VERSION 5.7 ;
BUSBITCHARS "[]" ;
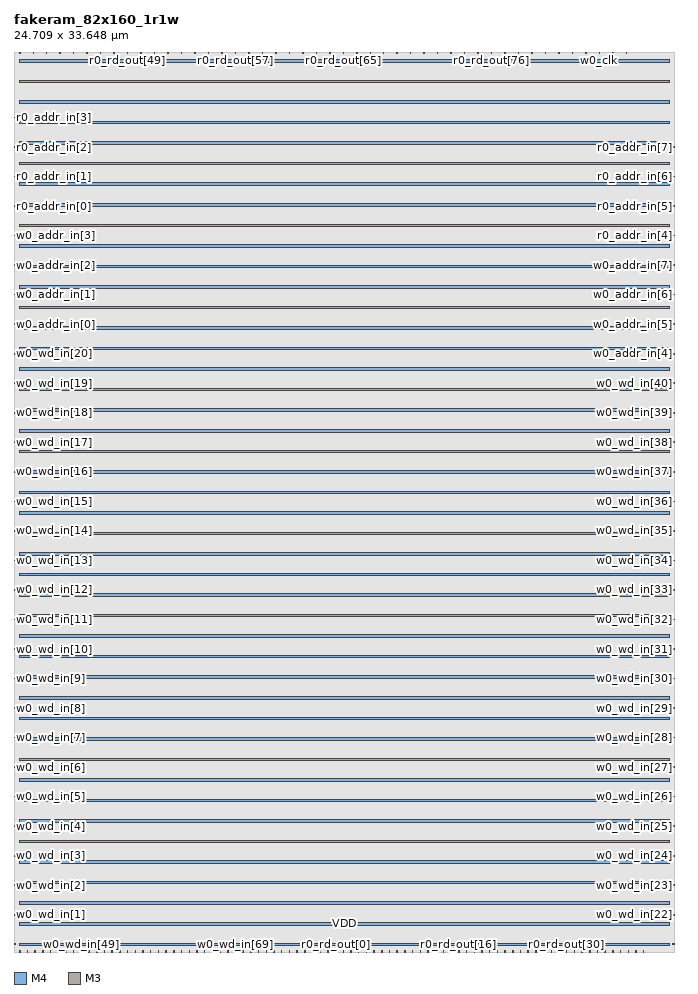
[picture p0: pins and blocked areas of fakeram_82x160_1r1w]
MACRO fakeram_82x160_1r1w
  FOREIGN fakeram_82x160_1r1w 0 0 ;
  SYMMETRY X Y R90 ;
  SIZE 24.709 BY 33.648 ;
  CLASS BLOCK ;
  PIN w0_wd_in[0]
    DIRECTION INPUT ;
    USE SIGNAL ;
    SHAPE ABUTMENT ;
    PORT
      LAYER M4 ;
      RECT 0.000 0.276 0.072 0.300 ;
    END
  END w0_wd_in[0]
  PIN w0_wd_in[1]
    DIRECTION INPUT ;
    USE SIGNAL ;
    SHAPE ABUTMENT ;
    PORT
      LAYER M4 ;
      RECT 0.000 1.380 0.072 1.404 ;
    END
  END w0_wd_in[1]
  PIN w0_wd_in[2]
    DIRECTION INPUT ;
    USE SIGNAL ;
    SHAPE ABUTMENT ;
    PORT
      LAYER M4 ;
      RECT 0.000 2.484 0.072 2.508 ;
    END
  END w0_wd_in[2]
  PIN w0_wd_in[3]
    DIRECTION INPUT ;
    USE SIGNAL ;
    SHAPE ABUTMENT ;
    PORT
      LAYER M4 ;
      RECT 0.000 3.588 0.072 3.612 ;
    END
  END w0_wd_in[3]
  PIN w0_wd_in[4]
    DIRECTION INPUT ;
    USE SIGNAL ;
    SHAPE ABUTMENT ;
    PORT
      LAYER M4 ;
      RECT 0.000 4.692 0.072 4.716 ;
    END
  END w0_wd_in[4]
  PIN w0_wd_in[5]
    DIRECTION INPUT ;
    USE SIGNAL ;
    SHAPE ABUTMENT ;
    PORT
      LAYER M4 ;
      RECT 0.000 5.796 0.072 5.820 ;
    END
  END w0_wd_in[5]
  PIN w0_wd_in[6]
    DIRECTION INPUT ;
    USE SIGNAL ;
    SHAPE ABUTMENT ;
    PORT
      LAYER M4 ;
      RECT 0.000 6.900 0.072 6.924 ;
    END
  END w0_wd_in[6]
  PIN w0_wd_in[7]
    DIRECTION INPUT ;
    USE SIGNAL ;
    SHAPE ABUTMENT ;
    PORT
      LAYER M4 ;
      RECT 0.000 8.004 0.072 8.028 ;
    END
  END w0_wd_in[7]
  PIN w0_wd_in[8]
    DIRECTION INPUT ;
    USE SIGNAL ;
    SHAPE ABUTMENT ;
    PORT
      LAYER M4 ;
      RECT 0.000 9.108 0.072 9.132 ;
    END
  END w0_wd_in[8]
  PIN w0_wd_in[9]
    DIRECTION INPUT ;
    USE SIGNAL ;
    SHAPE ABUTMENT ;
    PORT
      LAYER M4 ;
      RECT 0.000 10.212 0.072 10.236 ;
    END
  END w0_wd_in[9]
  PIN w0_wd_in[10]
    DIRECTION INPUT ;
    USE SIGNAL ;
    SHAPE ABUTMENT ;
    PORT
      LAYER M4 ;
      RECT 0.000 11.316 0.072 11.340 ;
    END
  END w0_wd_in[10]
  PIN w0_wd_in[11]
    DIRECTION INPUT ;
    USE SIGNAL ;
    SHAPE ABUTMENT ;
    PORT
      LAYER M4 ;
      RECT 0.000 12.420 0.072 12.444 ;
    END
  END w0_wd_in[11]
  PIN w0_wd_in[12]
    DIRECTION INPUT ;
    USE SIGNAL ;
    SHAPE ABUTMENT ;
    PORT
      LAYER M4 ;
      RECT 0.000 13.524 0.072 13.548 ;
    END
  END w0_wd_in[12]
  PIN w0_wd_in[13]
    DIRECTION INPUT ;
    USE SIGNAL ;
    SHAPE ABUTMENT ;
    PORT
      LAYER M4 ;
      RECT 0.000 14.628 0.072 14.652 ;
    END
  END w0_wd_in[13]
  PIN w0_wd_in[14]
    DIRECTION INPUT ;
    USE SIGNAL ;
    SHAPE ABUTMENT ;
    PORT
      LAYER M4 ;
      RECT 0.000 15.732 0.072 15.756 ;
    END
  END w0_wd_in[14]
  PIN w0_wd_in[15]
    DIRECTION INPUT ;
    USE SIGNAL ;
    SHAPE ABUTMENT ;
    PORT
      LAYER M4 ;
      RECT 0.000 16.836 0.072 16.860 ;
    END
  END w0_wd_in[15]
  PIN w0_wd_in[16]
    DIRECTION INPUT ;
    USE SIGNAL ;
    SHAPE ABUTMENT ;
    PORT
      LAYER M4 ;
      RECT 0.000 17.940 0.072 17.964 ;
    END
  END w0_wd_in[16]
  PIN w0_wd_in[17]
    DIRECTION INPUT ;
    USE SIGNAL ;
    SHAPE ABUTMENT ;
    PORT
      LAYER M4 ;
      RECT 0.000 19.044 0.072 19.068 ;
    END
  END w0_wd_in[17]
  PIN w0_wd_in[18]
    DIRECTION INPUT ;
    USE SIGNAL ;
    SHAPE ABUTMENT ;
    PORT
      LAYER M4 ;
      RECT 0.000 20.148 0.072 20.172 ;
    END
  END w0_wd_in[18]
  PIN w0_wd_in[19]
    DIRECTION INPUT ;
    USE SIGNAL ;
    SHAPE ABUTMENT ;
    PORT
      LAYER M4 ;
      RECT 0.000 21.252 0.072 21.276 ;
    END
  END w0_wd_in[19]
  PIN w0_wd_in[20]
    DIRECTION INPUT ;
    USE SIGNAL ;
    SHAPE ABUTMENT ;
    PORT
      LAYER M4 ;
      RECT 0.000 22.356 0.072 22.380 ;
    END
  END w0_wd_in[20]
  PIN w0_wd_in[21]
    DIRECTION INPUT ;
    USE SIGNAL ;
    SHAPE ABUTMENT ;
    PORT
      LAYER M4 ;
      RECT 24.637 0.276 24.709 0.300 ;
    END
  END w0_wd_in[21]
  PIN w0_wd_in[22]
    DIRECTION INPUT ;
    USE SIGNAL ;
    SHAPE ABUTMENT ;
    PORT
      LAYER M4 ;
      RECT 24.637 1.380 24.709 1.404 ;
    END
  END w0_wd_in[22]
  PIN w0_wd_in[23]
    DIRECTION INPUT ;
    USE SIGNAL ;
    SHAPE ABUTMENT ;
    PORT
      LAYER M4 ;
      RECT 24.637 2.484 24.709 2.508 ;
    END
  END w0_wd_in[23]
  PIN w0_wd_in[24]
    DIRECTION INPUT ;
    USE SIGNAL ;
    SHAPE ABUTMENT ;
    PORT
      LAYER M4 ;
      RECT 24.637 3.588 24.709 3.612 ;
    END
  END w0_wd_in[24]
  PIN w0_wd_in[25]
    DIRECTION INPUT ;
    USE SIGNAL ;
    SHAPE ABUTMENT ;
    PORT
      LAYER M4 ;
      RECT 24.637 4.692 24.709 4.716 ;
    END
  END w0_wd_in[25]
  PIN w0_wd_in[26]
    DIRECTION INPUT ;
    USE SIGNAL ;
    SHAPE ABUTMENT ;
    PORT
      LAYER M4 ;
      RECT 24.637 5.796 24.709 5.820 ;
    END
  END w0_wd_in[26]
  PIN w0_wd_in[27]
    DIRECTION INPUT ;
    USE SIGNAL ;
    SHAPE ABUTMENT ;
    PORT
      LAYER M4 ;
      RECT 24.637 6.900 24.709 6.924 ;
    END
  END w0_wd_in[27]
  PIN w0_wd_in[28]
    DIRECTION INPUT ;
    USE SIGNAL ;
    SHAPE ABUTMENT ;
    PORT
      LAYER M4 ;
      RECT 24.637 8.004 24.709 8.028 ;
    END
  END w0_wd_in[28]
  PIN w0_wd_in[29]
    DIRECTION INPUT ;
    USE SIGNAL ;
    SHAPE ABUTMENT ;
    PORT
      LAYER M4 ;
      RECT 24.637 9.108 24.709 9.132 ;
    END
  END w0_wd_in[29]
  PIN w0_wd_in[30]
    DIRECTION INPUT ;
    USE SIGNAL ;
    SHAPE ABUTMENT ;
    PORT
      LAYER M4 ;
      RECT 24.637 10.212 24.709 10.236 ;
    END
  END w0_wd_in[30]
  PIN w0_wd_in[31]
    DIRECTION INPUT ;
    USE SIGNAL ;
    SHAPE ABUTMENT ;
    PORT
      LAYER M4 ;
      RECT 24.637 11.316 24.709 11.340 ;
    END
  END w0_wd_in[31]
  PIN w0_wd_in[32]
    DIRECTION INPUT ;
    USE SIGNAL ;
    SHAPE ABUTMENT ;
    PORT
      LAYER M4 ;
      RECT 24.637 12.420 24.709 12.444 ;
    END
  END w0_wd_in[32]
  PIN w0_wd_in[33]
    DIRECTION INPUT ;
    USE SIGNAL ;
    SHAPE ABUTMENT ;
    PORT
      LAYER M4 ;
      RECT 24.637 13.524 24.709 13.548 ;
    END
  END w0_wd_in[33]
  PIN w0_wd_in[34]
    DIRECTION INPUT ;
    USE SIGNAL ;
    SHAPE ABUTMENT ;
    PORT
      LAYER M4 ;
      RECT 24.637 14.628 24.709 14.652 ;
    END
  END w0_wd_in[34]
  PIN w0_wd_in[35]
    DIRECTION INPUT ;
    USE SIGNAL ;
    SHAPE ABUTMENT ;
    PORT
      LAYER M4 ;
      RECT 24.637 15.732 24.709 15.756 ;
    END
  END w0_wd_in[35]
  PIN w0_wd_in[36]
    DIRECTION INPUT ;
    USE SIGNAL ;
    SHAPE ABUTMENT ;
    PORT
      LAYER M4 ;
      RECT 24.637 16.836 24.709 16.860 ;
    END
  END w0_wd_in[36]
  PIN w0_wd_in[37]
    DIRECTION INPUT ;
    USE SIGNAL ;
    SHAPE ABUTMENT ;
    PORT
      LAYER M4 ;
      RECT 24.637 17.940 24.709 17.964 ;
    END
  END w0_wd_in[37]
  PIN w0_wd_in[38]
    DIRECTION INPUT ;
    USE SIGNAL ;
    SHAPE ABUTMENT ;
    PORT
      LAYER M4 ;
      RECT 24.637 19.044 24.709 19.068 ;
    END
  END w0_wd_in[38]
  PIN w0_wd_in[39]
    DIRECTION INPUT ;
    USE SIGNAL ;
    SHAPE ABUTMENT ;
    PORT
      LAYER M4 ;
      RECT 24.637 20.148 24.709 20.172 ;
    END
  END w0_wd_in[39]
  PIN w0_wd_in[40]
    DIRECTION INPUT ;
    USE SIGNAL ;
    SHAPE ABUTMENT ;
    PORT
      LAYER M4 ;
      RECT 24.637 21.252 24.709 21.276 ;
    END
  END w0_wd_in[40]
  PIN w0_wd_in[41]
    DIRECTION OUTPUT ;
    USE SIGNAL ;
    SHAPE ABUTMENT ;
    PORT
      LAYER M3 ;
      RECT 0.207 0.000 0.225 0.054 ;
    END
  END w0_wd_in[41]
  PIN w0_wd_in[42]
    DIRECTION OUTPUT ;
    USE SIGNAL ;
    SHAPE ABUTMENT ;
    PORT
      LAYER M3 ;
      RECT 0.495 0.000 0.513 0.054 ;
    END
  END w0_wd_in[42]
  PIN w0_wd_in[43]
    DIRECTION OUTPUT ;
    USE SIGNAL ;
    SHAPE ABUTMENT ;
    PORT
      LAYER M3 ;
      RECT 0.783 0.000 0.801 0.054 ;
    END
  END w0_wd_in[43]
  PIN w0_wd_in[44]
    DIRECTION OUTPUT ;
    USE SIGNAL ;
    SHAPE ABUTMENT ;
    PORT
      LAYER M3 ;
      RECT 1.071 0.000 1.089 0.054 ;
    END
  END w0_wd_in[44]
  PIN w0_wd_in[45]
    DIRECTION OUTPUT ;
    USE SIGNAL ;
    SHAPE ABUTMENT ;
    PORT
      LAYER M3 ;
      RECT 1.359 0.000 1.377 0.054 ;
    END
  END w0_wd_in[45]
  PIN w0_wd_in[46]
    DIRECTION OUTPUT ;
    USE SIGNAL ;
    SHAPE ABUTMENT ;
    PORT
      LAYER M3 ;
      RECT 1.647 0.000 1.665 0.054 ;
    END
  END w0_wd_in[46]
  PIN w0_wd_in[47]
    DIRECTION OUTPUT ;
    USE SIGNAL ;
    SHAPE ABUTMENT ;
    PORT
      LAYER M3 ;
      RECT 1.935 0.000 1.953 0.054 ;
    END
  END w0_wd_in[47]
  PIN w0_wd_in[48]
    DIRECTION OUTPUT ;
    USE SIGNAL ;
    SHAPE ABUTMENT ;
    PORT
      LAYER M3 ;
      RECT 2.223 0.000 2.241 0.054 ;
    END
  END w0_wd_in[48]
  PIN w0_wd_in[49]
    DIRECTION OUTPUT ;
    USE SIGNAL ;
    SHAPE ABUTMENT ;
    PORT
      LAYER M3 ;
      RECT 2.511 0.000 2.529 0.054 ;
    END
  END w0_wd_in[49]
  PIN w0_wd_in[50]
    DIRECTION OUTPUT ;
    USE SIGNAL ;
    SHAPE ABUTMENT ;
    PORT
      LAYER M3 ;
      RECT 2.799 0.000 2.817 0.054 ;
    END
  END w0_wd_in[50]
  PIN w0_wd_in[51]
    DIRECTION OUTPUT ;
    USE SIGNAL ;
    SHAPE ABUTMENT ;
    PORT
      LAYER M3 ;
      RECT 3.087 0.000 3.105 0.054 ;
    END
  END w0_wd_in[51]
  PIN w0_wd_in[52]
    DIRECTION OUTPUT ;
    USE SIGNAL ;
    SHAPE ABUTMENT ;
    PORT
      LAYER M3 ;
      RECT 3.375 0.000 3.393 0.054 ;
    END
  END w0_wd_in[52]
  PIN w0_wd_in[53]
    DIRECTION OUTPUT ;
    USE SIGNAL ;
    SHAPE ABUTMENT ;
    PORT
      LAYER M3 ;
      RECT 3.663 0.000 3.681 0.054 ;
    END
  END w0_wd_in[53]
  PIN w0_wd_in[54]
    DIRECTION OUTPUT ;
    USE SIGNAL ;
    SHAPE ABUTMENT ;
    PORT
      LAYER M3 ;
      RECT 3.951 0.000 3.969 0.054 ;
    END
  END w0_wd_in[54]
  PIN w0_wd_in[55]
    DIRECTION OUTPUT ;
    USE SIGNAL ;
    SHAPE ABUTMENT ;
    PORT
      LAYER M3 ;
      RECT 4.239 0.000 4.257 0.054 ;
    END
  END w0_wd_in[55]
  PIN w0_wd_in[56]
    DIRECTION OUTPUT ;
    USE SIGNAL ;
    SHAPE ABUTMENT ;
    PORT
      LAYER M3 ;
      RECT 4.527 0.000 4.545 0.054 ;
    END
  END w0_wd_in[56]
  PIN w0_wd_in[57]
    DIRECTION OUTPUT ;
    USE SIGNAL ;
    SHAPE ABUTMENT ;
    PORT
      LAYER M3 ;
      RECT 4.815 0.000 4.833 0.054 ;
    END
  END w0_wd_in[57]
  PIN w0_wd_in[58]
    DIRECTION OUTPUT ;
    USE SIGNAL ;
    SHAPE ABUTMENT ;
    PORT
      LAYER M3 ;
      RECT 5.103 0.000 5.121 0.054 ;
    END
  END w0_wd_in[58]
  PIN w0_wd_in[59]
    DIRECTION OUTPUT ;
    USE SIGNAL ;
    SHAPE ABUTMENT ;
    PORT
      LAYER M3 ;
      RECT 5.391 0.000 5.409 0.054 ;
    END
  END w0_wd_in[59]
  PIN w0_wd_in[60]
    DIRECTION OUTPUT ;
    USE SIGNAL ;
    SHAPE ABUTMENT ;
    PORT
      LAYER M3 ;
      RECT 5.679 0.000 5.697 0.054 ;
    END
  END w0_wd_in[60]
  PIN w0_wd_in[61]
    DIRECTION OUTPUT ;
    USE SIGNAL ;
    SHAPE ABUTMENT ;
    PORT
      LAYER M3 ;
      RECT 5.967 0.000 5.985 0.054 ;
    END
  END w0_wd_in[61]
  PIN w0_wd_in[62]
    DIRECTION OUTPUT ;
    USE SIGNAL ;
    SHAPE ABUTMENT ;
    PORT
      LAYER M3 ;
      RECT 6.255 0.000 6.273 0.054 ;
    END
  END w0_wd_in[62]
  PIN w0_wd_in[63]
    DIRECTION OUTPUT ;
    USE SIGNAL ;
    SHAPE ABUTMENT ;
    PORT
      LAYER M3 ;
      RECT 6.543 0.000 6.561 0.054 ;
    END
  END w0_wd_in[63]
  PIN w0_wd_in[64]
    DIRECTION OUTPUT ;
    USE SIGNAL ;
    SHAPE ABUTMENT ;
    PORT
      LAYER M3 ;
      RECT 6.831 0.000 6.849 0.054 ;
    END
  END w0_wd_in[64]
  PIN w0_wd_in[65]
    DIRECTION OUTPUT ;
    USE SIGNAL ;
    SHAPE ABUTMENT ;
    PORT
      LAYER M3 ;
      RECT 7.119 0.000 7.137 0.054 ;
    END
  END w0_wd_in[65]
  PIN w0_wd_in[66]
    DIRECTION OUTPUT ;
    USE SIGNAL ;
    SHAPE ABUTMENT ;
    PORT
      LAYER M3 ;
      RECT 7.407 0.000 7.425 0.054 ;
    END
  END w0_wd_in[66]
  PIN w0_wd_in[67]
    DIRECTION OUTPUT ;
    USE SIGNAL ;
    SHAPE ABUTMENT ;
    PORT
      LAYER M3 ;
      RECT 7.695 0.000 7.713 0.054 ;
    END
  END w0_wd_in[67]
  PIN w0_wd_in[68]
    DIRECTION OUTPUT ;
    USE SIGNAL ;
    SHAPE ABUTMENT ;
    PORT
      LAYER M3 ;
      RECT 7.983 0.000 8.001 0.054 ;
    END
  END w0_wd_in[68]
  PIN w0_wd_in[69]
    DIRECTION OUTPUT ;
    USE SIGNAL ;
    SHAPE ABUTMENT ;
    PORT
      LAYER M3 ;
      RECT 8.271 0.000 8.289 0.054 ;
    END
  END w0_wd_in[69]
  PIN w0_wd_in[70]
    DIRECTION OUTPUT ;
    USE SIGNAL ;
    SHAPE ABUTMENT ;
    PORT
      LAYER M3 ;
      RECT 8.559 0.000 8.577 0.054 ;
    END
  END w0_wd_in[70]
  PIN w0_wd_in[71]
    DIRECTION OUTPUT ;
    USE SIGNAL ;
    SHAPE ABUTMENT ;
    PORT
      LAYER M3 ;
      RECT 8.847 0.000 8.865 0.054 ;
    END
  END w0_wd_in[71]
  PIN w0_wd_in[72]
    DIRECTION OUTPUT ;
    USE SIGNAL ;
    SHAPE ABUTMENT ;
    PORT
      LAYER M3 ;
      RECT 9.135 0.000 9.153 0.054 ;
    END
  END w0_wd_in[72]
  PIN w0_wd_in[73]
    DIRECTION OUTPUT ;
    USE SIGNAL ;
    SHAPE ABUTMENT ;
    PORT
      LAYER M3 ;
      RECT 9.423 0.000 9.441 0.054 ;
    END
  END w0_wd_in[73]
  PIN w0_wd_in[74]
    DIRECTION OUTPUT ;
    USE SIGNAL ;
    SHAPE ABUTMENT ;
    PORT
      LAYER M3 ;
      RECT 9.711 0.000 9.729 0.054 ;
    END
  END w0_wd_in[74]
  PIN w0_wd_in[75]
    DIRECTION OUTPUT ;
    USE SIGNAL ;
    SHAPE ABUTMENT ;
    PORT
      LAYER M3 ;
      RECT 9.999 0.000 10.017 0.054 ;
    END
  END w0_wd_in[75]
  PIN w0_wd_in[76]
    DIRECTION OUTPUT ;
    USE SIGNAL ;
    SHAPE ABUTMENT ;
    PORT
      LAYER M3 ;
      RECT 10.287 0.000 10.305 0.054 ;
    END
  END w0_wd_in[76]
  PIN w0_wd_in[77]
    DIRECTION OUTPUT ;
    USE SIGNAL ;
    SHAPE ABUTMENT ;
    PORT
      LAYER M3 ;
      RECT 10.575 0.000 10.593 0.054 ;
    END
  END w0_wd_in[77]
  PIN w0_wd_in[78]
    DIRECTION OUTPUT ;
    USE SIGNAL ;
    SHAPE ABUTMENT ;
    PORT
      LAYER M3 ;
      RECT 10.863 0.000 10.881 0.054 ;
    END
  END w0_wd_in[78]
  PIN w0_wd_in[79]
    DIRECTION OUTPUT ;
    USE SIGNAL ;
    SHAPE ABUTMENT ;
    PORT
      LAYER M3 ;
      RECT 11.151 0.000 11.169 0.054 ;
    END
  END w0_wd_in[79]
  PIN w0_wd_in[80]
    DIRECTION OUTPUT ;
    USE SIGNAL ;
    SHAPE ABUTMENT ;
    PORT
      LAYER M3 ;
      RECT 11.439 0.000 11.457 0.054 ;
    END
  END w0_wd_in[80]
  PIN w0_wd_in[81]
    DIRECTION OUTPUT ;
    USE SIGNAL ;
    SHAPE ABUTMENT ;
    PORT
      LAYER M3 ;
      RECT 11.727 0.000 11.745 0.054 ;
    END
  END w0_wd_in[81]
  PIN r0_rd_out[0]
    DIRECTION OUTPUT ;
    USE SIGNAL ;
    SHAPE ABUTMENT ;
    PORT
      LAYER M3 ;
      RECT 12.015 0.000 12.033 0.054 ;
    END
  END r0_rd_out[0]
  PIN r0_rd_out[1]
    DIRECTION OUTPUT ;
    USE SIGNAL ;
    SHAPE ABUTMENT ;
    PORT
      LAYER M3 ;
      RECT 12.303 0.000 12.321 0.054 ;
    END
  END r0_rd_out[1]
  PIN r0_rd_out[2]
    DIRECTION OUTPUT ;
    USE SIGNAL ;
    SHAPE ABUTMENT ;
    PORT
      LAYER M3 ;
      RECT 12.591 0.000 12.609 0.054 ;
    END
  END r0_rd_out[2]
  PIN r0_rd_out[3]
    DIRECTION OUTPUT ;
    USE SIGNAL ;
    SHAPE ABUTMENT ;
    PORT
      LAYER M3 ;
      RECT 12.879 0.000 12.897 0.054 ;
    END
  END r0_rd_out[3]
  PIN r0_rd_out[4]
    DIRECTION OUTPUT ;
    USE SIGNAL ;
    SHAPE ABUTMENT ;
    PORT
      LAYER M3 ;
      RECT 13.167 0.000 13.185 0.054 ;
    END
  END r0_rd_out[4]
  PIN r0_rd_out[5]
    DIRECTION OUTPUT ;
    USE SIGNAL ;
    SHAPE ABUTMENT ;
    PORT
      LAYER M3 ;
      RECT 13.455 0.000 13.473 0.054 ;
    END
  END r0_rd_out[5]
  PIN r0_rd_out[6]
    DIRECTION OUTPUT ;
    USE SIGNAL ;
    SHAPE ABUTMENT ;
    PORT
      LAYER M3 ;
      RECT 13.743 0.000 13.761 0.054 ;
    END
  END r0_rd_out[6]
  PIN r0_rd_out[7]
    DIRECTION OUTPUT ;
    USE SIGNAL ;
    SHAPE ABUTMENT ;
    PORT
      LAYER M3 ;
      RECT 14.031 0.000 14.049 0.054 ;
    END
  END r0_rd_out[7]
  PIN r0_rd_out[8]
    DIRECTION OUTPUT ;
    USE SIGNAL ;
    SHAPE ABUTMENT ;
    PORT
      LAYER M3 ;
      RECT 14.319 0.000 14.337 0.054 ;
    END
  END r0_rd_out[8]
  PIN r0_rd_out[9]
    DIRECTION OUTPUT ;
    USE SIGNAL ;
    SHAPE ABUTMENT ;
    PORT
      LAYER M3 ;
      RECT 14.607 0.000 14.625 0.054 ;
    END
  END r0_rd_out[9]
  PIN r0_rd_out[10]
    DIRECTION OUTPUT ;
    USE SIGNAL ;
    SHAPE ABUTMENT ;
    PORT
      LAYER M3 ;
      RECT 14.895 0.000 14.913 0.054 ;
    END
  END r0_rd_out[10]
  PIN r0_rd_out[11]
    DIRECTION OUTPUT ;
    USE SIGNAL ;
    SHAPE ABUTMENT ;
    PORT
      LAYER M3 ;
      RECT 15.183 0.000 15.201 0.054 ;
    END
  END r0_rd_out[11]
  PIN r0_rd_out[12]
    DIRECTION OUTPUT ;
    USE SIGNAL ;
    SHAPE ABUTMENT ;
    PORT
      LAYER M3 ;
      RECT 15.471 0.000 15.489 0.054 ;
    END
  END r0_rd_out[12]
  PIN r0_rd_out[13]
    DIRECTION OUTPUT ;
    USE SIGNAL ;
    SHAPE ABUTMENT ;
    PORT
      LAYER M3 ;
      RECT 15.759 0.000 15.777 0.054 ;
    END
  END r0_rd_out[13]
  PIN r0_rd_out[14]
    DIRECTION OUTPUT ;
    USE SIGNAL ;
    SHAPE ABUTMENT ;
    PORT
      LAYER M3 ;
      RECT 16.047 0.000 16.065 0.054 ;
    END
  END r0_rd_out[14]
  PIN r0_rd_out[15]
    DIRECTION OUTPUT ;
    USE SIGNAL ;
    SHAPE ABUTMENT ;
    PORT
      LAYER M3 ;
      RECT 16.335 0.000 16.353 0.054 ;
    END
  END r0_rd_out[15]
  PIN r0_rd_out[16]
    DIRECTION OUTPUT ;
    USE SIGNAL ;
    SHAPE ABUTMENT ;
    PORT
      LAYER M3 ;
      RECT 16.623 0.000 16.641 0.054 ;
    END
  END r0_rd_out[16]
  PIN r0_rd_out[17]
    DIRECTION OUTPUT ;
    USE SIGNAL ;
    SHAPE ABUTMENT ;
    PORT
      LAYER M3 ;
      RECT 16.911 0.000 16.929 0.054 ;
    END
  END r0_rd_out[17]
  PIN r0_rd_out[18]
    DIRECTION OUTPUT ;
    USE SIGNAL ;
    SHAPE ABUTMENT ;
    PORT
      LAYER M3 ;
      RECT 17.199 0.000 17.217 0.054 ;
    END
  END r0_rd_out[18]
  PIN r0_rd_out[19]
    DIRECTION OUTPUT ;
    USE SIGNAL ;
    SHAPE ABUTMENT ;
    PORT
      LAYER M3 ;
      RECT 17.487 0.000 17.505 0.054 ;
    END
  END r0_rd_out[19]
  PIN r0_rd_out[20]
    DIRECTION OUTPUT ;
    USE SIGNAL ;
    SHAPE ABUTMENT ;
    PORT
      LAYER M3 ;
      RECT 17.775 0.000 17.793 0.054 ;
    END
  END r0_rd_out[20]
  PIN r0_rd_out[21]
    DIRECTION OUTPUT ;
    USE SIGNAL ;
    SHAPE ABUTMENT ;
    PORT
      LAYER M3 ;
      RECT 18.063 0.000 18.081 0.054 ;
    END
  END r0_rd_out[21]
  PIN r0_rd_out[22]
    DIRECTION OUTPUT ;
    USE SIGNAL ;
    SHAPE ABUTMENT ;
    PORT
      LAYER M3 ;
      RECT 18.351 0.000 18.369 0.054 ;
    END
  END r0_rd_out[22]
  PIN r0_rd_out[23]
    DIRECTION OUTPUT ;
    USE SIGNAL ;
    SHAPE ABUTMENT ;
    PORT
      LAYER M3 ;
      RECT 18.639 0.000 18.657 0.054 ;
    END
  END r0_rd_out[23]
  PIN r0_rd_out[24]
    DIRECTION OUTPUT ;
    USE SIGNAL ;
    SHAPE ABUTMENT ;
    PORT
      LAYER M3 ;
      RECT 18.927 0.000 18.945 0.054 ;
    END
  END r0_rd_out[24]
  PIN r0_rd_out[25]
    DIRECTION OUTPUT ;
    USE SIGNAL ;
    SHAPE ABUTMENT ;
    PORT
      LAYER M3 ;
      RECT 19.215 0.000 19.233 0.054 ;
    END
  END r0_rd_out[25]
  PIN r0_rd_out[26]
    DIRECTION OUTPUT ;
    USE SIGNAL ;
    SHAPE ABUTMENT ;
    PORT
      LAYER M3 ;
      RECT 19.503 0.000 19.521 0.054 ;
    END
  END r0_rd_out[26]
  PIN r0_rd_out[27]
    DIRECTION OUTPUT ;
    USE SIGNAL ;
    SHAPE ABUTMENT ;
    PORT
      LAYER M3 ;
      RECT 19.791 0.000 19.809 0.054 ;
    END
  END r0_rd_out[27]
  PIN r0_rd_out[28]
    DIRECTION OUTPUT ;
    USE SIGNAL ;
    SHAPE ABUTMENT ;
    PORT
      LAYER M3 ;
      RECT 20.079 0.000 20.097 0.054 ;
    END
  END r0_rd_out[28]
  PIN r0_rd_out[29]
    DIRECTION OUTPUT ;
    USE SIGNAL ;
    SHAPE ABUTMENT ;
    PORT
      LAYER M3 ;
      RECT 20.367 0.000 20.385 0.054 ;
    END
  END r0_rd_out[29]
  PIN r0_rd_out[30]
    DIRECTION OUTPUT ;
    USE SIGNAL ;
    SHAPE ABUTMENT ;
    PORT
      LAYER M3 ;
      RECT 20.655 0.000 20.673 0.054 ;
    END
  END r0_rd_out[30]
  PIN r0_rd_out[31]
    DIRECTION OUTPUT ;
    USE SIGNAL ;
    SHAPE ABUTMENT ;
    PORT
      LAYER M3 ;
      RECT 20.943 0.000 20.961 0.054 ;
    END
  END r0_rd_out[31]
  PIN r0_rd_out[32]
    DIRECTION OUTPUT ;
    USE SIGNAL ;
    SHAPE ABUTMENT ;
    PORT
      LAYER M3 ;
      RECT 21.231 0.000 21.249 0.054 ;
    END
  END r0_rd_out[32]
  PIN r0_rd_out[33]
    DIRECTION OUTPUT ;
    USE SIGNAL ;
    SHAPE ABUTMENT ;
    PORT
      LAYER M3 ;
      RECT 21.519 0.000 21.537 0.054 ;
    END
  END r0_rd_out[33]
  PIN r0_rd_out[34]
    DIRECTION OUTPUT ;
    USE SIGNAL ;
    SHAPE ABUTMENT ;
    PORT
      LAYER M3 ;
      RECT 21.807 0.000 21.825 0.054 ;
    END
  END r0_rd_out[34]
  PIN r0_rd_out[35]
    DIRECTION OUTPUT ;
    USE SIGNAL ;
    SHAPE ABUTMENT ;
    PORT
      LAYER M3 ;
      RECT 22.095 0.000 22.113 0.054 ;
    END
  END r0_rd_out[35]
  PIN r0_rd_out[36]
    DIRECTION OUTPUT ;
    USE SIGNAL ;
    SHAPE ABUTMENT ;
    PORT
      LAYER M3 ;
      RECT 22.383 0.000 22.401 0.054 ;
    END
  END r0_rd_out[36]
  PIN r0_rd_out[37]
    DIRECTION OUTPUT ;
    USE SIGNAL ;
    SHAPE ABUTMENT ;
    PORT
      LAYER M3 ;
      RECT 22.671 0.000 22.689 0.054 ;
    END
  END r0_rd_out[37]
  PIN r0_rd_out[38]
    DIRECTION OUTPUT ;
    USE SIGNAL ;
    SHAPE ABUTMENT ;
    PORT
      LAYER M3 ;
      RECT 22.959 0.000 22.977 0.054 ;
    END
  END r0_rd_out[38]
  PIN r0_rd_out[39]
    DIRECTION OUTPUT ;
    USE SIGNAL ;
    SHAPE ABUTMENT ;
    PORT
      LAYER M3 ;
      RECT 23.247 0.000 23.265 0.054 ;
    END
  END r0_rd_out[39]
  PIN r0_rd_out[40]
    DIRECTION OUTPUT ;
    USE SIGNAL ;
    SHAPE ABUTMENT ;
    PORT
      LAYER M3 ;
      RECT 23.535 0.000 23.553 0.054 ;
    END
  END r0_rd_out[40]
  PIN r0_rd_out[41]
    DIRECTION OUTPUT ;
    USE SIGNAL ;
    SHAPE ABUTMENT ;
    PORT
      LAYER M3 ;
      RECT 0.207 33.594 0.225 33.648 ;
    END
  END r0_rd_out[41]
  PIN r0_rd_out[42]
    DIRECTION OUTPUT ;
    USE SIGNAL ;
    SHAPE ABUTMENT ;
    PORT
      LAYER M3 ;
      RECT 0.711 33.594 0.729 33.648 ;
    END
  END r0_rd_out[42]
  PIN r0_rd_out[43]
    DIRECTION OUTPUT ;
    USE SIGNAL ;
    SHAPE ABUTMENT ;
    PORT
      LAYER M3 ;
      RECT 1.215 33.594 1.233 33.648 ;
    END
  END r0_rd_out[43]
  PIN r0_rd_out[44]
    DIRECTION OUTPUT ;
    USE SIGNAL ;
    SHAPE ABUTMENT ;
    PORT
      LAYER M3 ;
      RECT 1.719 33.594 1.737 33.648 ;
    END
  END r0_rd_out[44]
  PIN r0_rd_out[45]
    DIRECTION OUTPUT ;
    USE SIGNAL ;
    SHAPE ABUTMENT ;
    PORT
      LAYER M3 ;
      RECT 2.223 33.594 2.241 33.648 ;
    END
  END r0_rd_out[45]
  PIN r0_rd_out[46]
    DIRECTION OUTPUT ;
    USE SIGNAL ;
    SHAPE ABUTMENT ;
    PORT
      LAYER M3 ;
      RECT 2.727 33.594 2.745 33.648 ;
    END
  END r0_rd_out[46]
  PIN r0_rd_out[47]
    DIRECTION OUTPUT ;
    USE SIGNAL ;
    SHAPE ABUTMENT ;
    PORT
      LAYER M3 ;
      RECT 3.231 33.594 3.249 33.648 ;
    END
  END r0_rd_out[47]
  PIN r0_rd_out[48]
    DIRECTION OUTPUT ;
    USE SIGNAL ;
    SHAPE ABUTMENT ;
    PORT
      LAYER M3 ;
      RECT 3.735 33.594 3.753 33.648 ;
    END
  END r0_rd_out[48]
  PIN r0_rd_out[49]
    DIRECTION OUTPUT ;
    USE SIGNAL ;
    SHAPE ABUTMENT ;
    PORT
      LAYER M3 ;
      RECT 4.239 33.594 4.257 33.648 ;
    END
  END r0_rd_out[49]
  PIN r0_rd_out[50]
    DIRECTION OUTPUT ;
    USE SIGNAL ;
    SHAPE ABUTMENT ;
    PORT
      LAYER M3 ;
      RECT 4.743 33.594 4.761 33.648 ;
    END
  END r0_rd_out[50]
  PIN r0_rd_out[51]
    DIRECTION OUTPUT ;
    USE SIGNAL ;
    SHAPE ABUTMENT ;
    PORT
      LAYER M3 ;
      RECT 5.247 33.594 5.265 33.648 ;
    END
  END r0_rd_out[51]
  PIN r0_rd_out[52]
    DIRECTION OUTPUT ;
    USE SIGNAL ;
    SHAPE ABUTMENT ;
    PORT
      LAYER M3 ;
      RECT 5.751 33.594 5.769 33.648 ;
    END
  END r0_rd_out[52]
  PIN r0_rd_out[53]
    DIRECTION OUTPUT ;
    USE SIGNAL ;
    SHAPE ABUTMENT ;
    PORT
      LAYER M3 ;
      RECT 6.255 33.594 6.273 33.648 ;
    END
  END r0_rd_out[53]
  PIN r0_rd_out[54]
    DIRECTION OUTPUT ;
    USE SIGNAL ;
    SHAPE ABUTMENT ;
    PORT
      LAYER M3 ;
      RECT 6.759 33.594 6.777 33.648 ;
    END
  END r0_rd_out[54]
  PIN r0_rd_out[55]
    DIRECTION OUTPUT ;
    USE SIGNAL ;
    SHAPE ABUTMENT ;
    PORT
      LAYER M3 ;
      RECT 7.263 33.594 7.281 33.648 ;
    END
  END r0_rd_out[55]
  PIN r0_rd_out[56]
    DIRECTION OUTPUT ;
    USE SIGNAL ;
    SHAPE ABUTMENT ;
    PORT
      LAYER M3 ;
      RECT 7.767 33.594 7.785 33.648 ;
    END
  END r0_rd_out[56]
  PIN r0_rd_out[57]
    DIRECTION OUTPUT ;
    USE SIGNAL ;
    SHAPE ABUTMENT ;
    PORT
      LAYER M3 ;
      RECT 8.271 33.594 8.289 33.648 ;
    END
  END r0_rd_out[57]
  PIN r0_rd_out[58]
    DIRECTION OUTPUT ;
    USE SIGNAL ;
    SHAPE ABUTMENT ;
    PORT
      LAYER M3 ;
      RECT 8.775 33.594 8.793 33.648 ;
    END
  END r0_rd_out[58]
  PIN r0_rd_out[59]
    DIRECTION OUTPUT ;
    USE SIGNAL ;
    SHAPE ABUTMENT ;
    PORT
      LAYER M3 ;
      RECT 9.279 33.594 9.297 33.648 ;
    END
  END r0_rd_out[59]
  PIN r0_rd_out[60]
    DIRECTION OUTPUT ;
    USE SIGNAL ;
    SHAPE ABUTMENT ;
    PORT
      LAYER M3 ;
      RECT 9.783 33.594 9.801 33.648 ;
    END
  END r0_rd_out[60]
  PIN r0_rd_out[61]
    DIRECTION OUTPUT ;
    USE SIGNAL ;
    SHAPE ABUTMENT ;
    PORT
      LAYER M3 ;
      RECT 10.287 33.594 10.305 33.648 ;
    END
  END r0_rd_out[61]
  PIN r0_rd_out[62]
    DIRECTION OUTPUT ;
    USE SIGNAL ;
    SHAPE ABUTMENT ;
    PORT
      LAYER M3 ;
      RECT 10.791 33.594 10.809 33.648 ;
    END
  END r0_rd_out[62]
  PIN r0_rd_out[63]
    DIRECTION OUTPUT ;
    USE SIGNAL ;
    SHAPE ABUTMENT ;
    PORT
      LAYER M3 ;
      RECT 11.295 33.594 11.313 33.648 ;
    END
  END r0_rd_out[63]
  PIN r0_rd_out[64]
    DIRECTION OUTPUT ;
    USE SIGNAL ;
    SHAPE ABUTMENT ;
    PORT
      LAYER M3 ;
      RECT 11.799 33.594 11.817 33.648 ;
    END
  END r0_rd_out[64]
  PIN r0_rd_out[65]
    DIRECTION OUTPUT ;
    USE SIGNAL ;
    SHAPE ABUTMENT ;
    PORT
      LAYER M3 ;
      RECT 12.303 33.594 12.321 33.648 ;
    END
  END r0_rd_out[65]
  PIN r0_rd_out[66]
    DIRECTION OUTPUT ;
    USE SIGNAL ;
    SHAPE ABUTMENT ;
    PORT
      LAYER M3 ;
      RECT 12.807 33.594 12.825 33.648 ;
    END
  END r0_rd_out[66]
  PIN r0_rd_out[67]
    DIRECTION OUTPUT ;
    USE SIGNAL ;
    SHAPE ABUTMENT ;
    PORT
      LAYER M3 ;
      RECT 13.311 33.594 13.329 33.648 ;
    END
  END r0_rd_out[67]
  PIN r0_rd_out[68]
    DIRECTION OUTPUT ;
    USE SIGNAL ;
    SHAPE ABUTMENT ;
    PORT
      LAYER M3 ;
      RECT 13.815 33.594 13.833 33.648 ;
    END
  END r0_rd_out[68]
  PIN r0_rd_out[69]
    DIRECTION OUTPUT ;
    USE SIGNAL ;
    SHAPE ABUTMENT ;
    PORT
      LAYER M3 ;
      RECT 14.319 33.594 14.337 33.648 ;
    END
  END r0_rd_out[69]
  PIN r0_rd_out[70]
    DIRECTION OUTPUT ;
    USE SIGNAL ;
    SHAPE ABUTMENT ;
    PORT
      LAYER M3 ;
      RECT 14.823 33.594 14.841 33.648 ;
    END
  END r0_rd_out[70]
  PIN r0_rd_out[71]
    DIRECTION OUTPUT ;
    USE SIGNAL ;
    SHAPE ABUTMENT ;
    PORT
      LAYER M3 ;
      RECT 15.327 33.594 15.345 33.648 ;
    END
  END r0_rd_out[71]
  PIN r0_rd_out[72]
    DIRECTION OUTPUT ;
    USE SIGNAL ;
    SHAPE ABUTMENT ;
    PORT
      LAYER M3 ;
      RECT 15.831 33.594 15.849 33.648 ;
    END
  END r0_rd_out[72]
  PIN r0_rd_out[73]
    DIRECTION OUTPUT ;
    USE SIGNAL ;
    SHAPE ABUTMENT ;
    PORT
      LAYER M3 ;
      RECT 16.335 33.594 16.353 33.648 ;
    END
  END r0_rd_out[73]
  PIN r0_rd_out[74]
    DIRECTION OUTPUT ;
    USE SIGNAL ;
    SHAPE ABUTMENT ;
    PORT
      LAYER M3 ;
      RECT 16.839 33.594 16.857 33.648 ;
    END
  END r0_rd_out[74]
  PIN r0_rd_out[75]
    DIRECTION OUTPUT ;
    USE SIGNAL ;
    SHAPE ABUTMENT ;
    PORT
      LAYER M3 ;
      RECT 17.343 33.594 17.361 33.648 ;
    END
  END r0_rd_out[75]
  PIN r0_rd_out[76]
    DIRECTION OUTPUT ;
    USE SIGNAL ;
    SHAPE ABUTMENT ;
    PORT
      LAYER M3 ;
      RECT 17.847 33.594 17.865 33.648 ;
    END
  END r0_rd_out[76]
  PIN r0_rd_out[77]
    DIRECTION OUTPUT ;
    USE SIGNAL ;
    SHAPE ABUTMENT ;
    PORT
      LAYER M3 ;
      RECT 18.351 33.594 18.369 33.648 ;
    END
  END r0_rd_out[77]
  PIN r0_rd_out[78]
    DIRECTION OUTPUT ;
    USE SIGNAL ;
    SHAPE ABUTMENT ;
    PORT
      LAYER M3 ;
      RECT 18.855 33.594 18.873 33.648 ;
    END
  END r0_rd_out[78]
  PIN r0_rd_out[79]
    DIRECTION OUTPUT ;
    USE SIGNAL ;
    SHAPE ABUTMENT ;
    PORT
      LAYER M3 ;
      RECT 19.359 33.594 19.377 33.648 ;
    END
  END r0_rd_out[79]
  PIN r0_rd_out[80]
    DIRECTION OUTPUT ;
    USE SIGNAL ;
    SHAPE ABUTMENT ;
    PORT
      LAYER M3 ;
      RECT 19.863 33.594 19.881 33.648 ;
    END
  END r0_rd_out[80]
  PIN r0_rd_out[81]
    DIRECTION OUTPUT ;
    USE SIGNAL ;
    SHAPE ABUTMENT ;
    PORT
      LAYER M3 ;
      RECT 20.367 33.594 20.385 33.648 ;
    END
  END r0_rd_out[81]
  PIN w0_addr_in[0]
    DIRECTION INPUT ;
    USE SIGNAL ;
    SHAPE ABUTMENT ;
    PORT
      LAYER M4 ;
      RECT 0.000 23.460 0.072 23.484 ;
    END
  END w0_addr_in[0]
  PIN w0_addr_in[1]
    DIRECTION INPUT ;
    USE SIGNAL ;
    SHAPE ABUTMENT ;
    PORT
      LAYER M4 ;
      RECT 0.000 24.564 0.072 24.588 ;
    END
  END w0_addr_in[1]
  PIN w0_addr_in[2]
    DIRECTION INPUT ;
    USE SIGNAL ;
    SHAPE ABUTMENT ;
    PORT
      LAYER M4 ;
      RECT 0.000 25.668 0.072 25.692 ;
    END
  END w0_addr_in[2]
  PIN w0_addr_in[3]
    DIRECTION INPUT ;
    USE SIGNAL ;
    SHAPE ABUTMENT ;
    PORT
      LAYER M4 ;
      RECT 0.000 26.772 0.072 26.796 ;
    END
  END w0_addr_in[3]
  PIN w0_addr_in[4]
    DIRECTION INPUT ;
    USE SIGNAL ;
    SHAPE ABUTMENT ;
    PORT
      LAYER M4 ;
      RECT 24.637 22.356 24.709 22.380 ;
    END
  END w0_addr_in[4]
  PIN w0_addr_in[5]
    DIRECTION INPUT ;
    USE SIGNAL ;
    SHAPE ABUTMENT ;
    PORT
      LAYER M4 ;
      RECT 24.637 23.460 24.709 23.484 ;
    END
  END w0_addr_in[5]
  PIN w0_addr_in[6]
    DIRECTION INPUT ;
    USE SIGNAL ;
    SHAPE ABUTMENT ;
    PORT
      LAYER M4 ;
      RECT 24.637 24.564 24.709 24.588 ;
    END
  END w0_addr_in[6]
  PIN w0_addr_in[7]
    DIRECTION INPUT ;
    USE SIGNAL ;
    SHAPE ABUTMENT ;
    PORT
      LAYER M4 ;
      RECT 24.637 25.668 24.709 25.692 ;
    END
  END w0_addr_in[7]
  PIN r0_addr_in[0]
    DIRECTION INPUT ;
    USE SIGNAL ;
    SHAPE ABUTMENT ;
    PORT
      LAYER M4 ;
      RECT 0.000 27.876 0.072 27.900 ;
    END
  END r0_addr_in[0]
  PIN r0_addr_in[1]
    DIRECTION INPUT ;
    USE SIGNAL ;
    SHAPE ABUTMENT ;
    PORT
      LAYER M4 ;
      RECT 0.000 28.980 0.072 29.004 ;
    END
  END r0_addr_in[1]
  PIN r0_addr_in[2]
    DIRECTION INPUT ;
    USE SIGNAL ;
    SHAPE ABUTMENT ;
    PORT
      LAYER M4 ;
      RECT 0.000 30.084 0.072 30.108 ;
    END
  END r0_addr_in[2]
  PIN r0_addr_in[3]
    DIRECTION INPUT ;
    USE SIGNAL ;
    SHAPE ABUTMENT ;
    PORT
      LAYER M4 ;
      RECT 0.000 31.188 0.072 31.212 ;
    END
  END r0_addr_in[3]
  PIN r0_addr_in[4]
    DIRECTION INPUT ;
    USE SIGNAL ;
    SHAPE ABUTMENT ;
    PORT
      LAYER M4 ;
      RECT 24.637 26.772 24.709 26.796 ;
    END
  END r0_addr_in[4]
  PIN r0_addr_in[5]
    DIRECTION INPUT ;
    USE SIGNAL ;
    SHAPE ABUTMENT ;
    PORT
      LAYER M4 ;
      RECT 24.637 27.876 24.709 27.900 ;
    END
  END r0_addr_in[5]
  PIN r0_addr_in[6]
    DIRECTION INPUT ;
    USE SIGNAL ;
    SHAPE ABUTMENT ;
    PORT
      LAYER M4 ;
      RECT 24.637 28.980 24.709 29.004 ;
    END
  END r0_addr_in[6]
  PIN r0_addr_in[7]
    DIRECTION INPUT ;
    USE SIGNAL ;
    SHAPE ABUTMENT ;
    PORT
      LAYER M4 ;
      RECT 24.637 30.084 24.709 30.108 ;
    END
  END r0_addr_in[7]
  PIN w0_we_in
    DIRECTION INPUT ;
    USE SIGNAL ;
    SHAPE ABUTMENT ;
    PORT
      LAYER M3 ;
      RECT 20.871 33.594 20.889 33.648 ;
    END
  END w0_we_in
  PIN w0_ce_in
    DIRECTION INPUT ;
    USE SIGNAL ;
    SHAPE ABUTMENT ;
    PORT
      LAYER M3 ;
      RECT 21.375 33.594 21.393 33.648 ;
    END
  END w0_ce_in
  PIN w0_clk
    DIRECTION INPUT ;
    USE SIGNAL ;
    SHAPE ABUTMENT ;
    PORT
      LAYER M3 ;
      RECT 21.879 33.594 21.897 33.648 ;
    END
  END w0_clk
  PIN r0_ce_in
    DIRECTION INPUT ;
    USE SIGNAL ;
    SHAPE ABUTMENT ;
    PORT
      LAYER M3 ;
      RECT 22.383 33.594 22.401 33.648 ;
    END
  END r0_ce_in
  PIN r0_clk
    DIRECTION INPUT ;
    USE SIGNAL ;
    SHAPE ABUTMENT ;
    PORT
      LAYER M3 ;
      RECT 22.887 33.594 22.905 33.648 ;
    END
  END r0_clk
  PIN VSS
    DIRECTION INOUT ;
    USE GROUND ;
    PORT
      LAYER M4 ;
      RECT 0.216 0.240 24.493 0.336 ;
      RECT 0.216 1.008 24.493 1.104 ;
      RECT 0.216 1.776 24.493 1.872 ;
      RECT 0.216 2.544 24.493 2.640 ;
      RECT 0.216 3.312 24.493 3.408 ;
      RECT 0.216 4.080 24.493 4.176 ;
      RECT 0.216 4.848 24.493 4.944 ;
      RECT 0.216 5.616 24.493 5.712 ;
      RECT 0.216 6.384 24.493 6.480 ;
      RECT 0.216 7.152 24.493 7.248 ;
      RECT 0.216 7.920 24.493 8.016 ;
      RECT 0.216 8.688 24.493 8.784 ;
      RECT 0.216 9.456 24.493 9.552 ;
      RECT 0.216 10.224 24.493 10.320 ;
      RECT 0.216 10.992 24.493 11.088 ;
      RECT 0.216 11.760 24.493 11.856 ;
      RECT 0.216 12.528 24.493 12.624 ;
      RECT 0.216 13.296 24.493 13.392 ;
      RECT 0.216 14.064 24.493 14.160 ;
      RECT 0.216 14.832 24.493 14.928 ;
      RECT 0.216 15.600 24.493 15.696 ;
      RECT 0.216 16.368 24.493 16.464 ;
      RECT 0.216 17.136 24.493 17.232 ;
      RECT 0.216 17.904 24.493 18.000 ;
      RECT 0.216 18.672 24.493 18.768 ;
      RECT 0.216 19.440 24.493 19.536 ;
      RECT 0.216 20.208 24.493 20.304 ;
      RECT 0.216 20.976 24.493 21.072 ;
      RECT 0.216 21.744 24.493 21.840 ;
      RECT 0.216 22.512 24.493 22.608 ;
      RECT 0.216 23.280 24.493 23.376 ;
      RECT 0.216 24.048 24.493 24.144 ;
      RECT 0.216 24.816 24.493 24.912 ;
      RECT 0.216 25.584 24.493 25.680 ;
      RECT 0.216 26.352 24.493 26.448 ;
      RECT 0.216 27.120 24.493 27.216 ;
      RECT 0.216 27.888 24.493 27.984 ;
      RECT 0.216 28.656 24.493 28.752 ;
      RECT 0.216 29.424 24.493 29.520 ;
      RECT 0.216 30.192 24.493 30.288 ;
      RECT 0.216 30.960 24.493 31.056 ;
      RECT 0.216 31.728 24.493 31.824 ;
      RECT 0.216 32.496 24.493 32.592 ;
      RECT 0.216 33.264 24.493 33.360 ;
    END
  END VSS
  PIN VDD
    DIRECTION INOUT ;
    USE POWER ;
    PORT
      LAYER M4 ;
      RECT 0.216 0.240 24.493 0.336 ;
      RECT 0.216 1.008 24.493 1.104 ;
      RECT 0.216 1.776 24.493 1.872 ;
      RECT 0.216 2.544 24.493 2.640 ;
      RECT 0.216 3.312 24.493 3.408 ;
      RECT 0.216 4.080 24.493 4.176 ;
      RECT 0.216 4.848 24.493 4.944 ;
      RECT 0.216 5.616 24.493 5.712 ;
      RECT 0.216 6.384 24.493 6.480 ;
      RECT 0.216 7.152 24.493 7.248 ;
      RECT 0.216 7.920 24.493 8.016 ;
      RECT 0.216 8.688 24.493 8.784 ;
      RECT 0.216 9.456 24.493 9.552 ;
      RECT 0.216 10.224 24.493 10.320 ;
      RECT 0.216 10.992 24.493 11.088 ;
      RECT 0.216 11.760 24.493 11.856 ;
      RECT 0.216 12.528 24.493 12.624 ;
      RECT 0.216 13.296 24.493 13.392 ;
      RECT 0.216 14.064 24.493 14.160 ;
      RECT 0.216 14.832 24.493 14.928 ;
      RECT 0.216 15.600 24.493 15.696 ;
      RECT 0.216 16.368 24.493 16.464 ;
      RECT 0.216 17.136 24.493 17.232 ;
      RECT 0.216 17.904 24.493 18.000 ;
      RECT 0.216 18.672 24.493 18.768 ;
      RECT 0.216 19.440 24.493 19.536 ;
      RECT 0.216 20.208 24.493 20.304 ;
      RECT 0.216 20.976 24.493 21.072 ;
      RECT 0.216 21.744 24.493 21.840 ;
      RECT 0.216 22.512 24.493 22.608 ;
      RECT 0.216 23.280 24.493 23.376 ;
      RECT 0.216 24.048 24.493 24.144 ;
      RECT 0.216 24.816 24.493 24.912 ;
      RECT 0.216 25.584 24.493 25.680 ;
      RECT 0.216 26.352 24.493 26.448 ;
      RECT 0.216 27.120 24.493 27.216 ;
      RECT 0.216 27.888 24.493 27.984 ;
      RECT 0.216 28.656 24.493 28.752 ;
      RECT 0.216 29.424 24.493 29.520 ;
      RECT 0.216 30.192 24.493 30.288 ;
      RECT 0.216 30.960 24.493 31.056 ;
      RECT 0.216 31.728 24.493 31.824 ;
      RECT 0.216 32.496 24.493 32.592 ;
      RECT 0.216 33.264 24.493 33.360 ;
    END
  END VDD
  OBS
    LAYER M1 ;
    RECT 0 0 24.709 33.648 ;
    LAYER M2 ;
    RECT 0 0 24.709 33.648 ;
    LAYER M3 ;
    RECT 0 0 24.709 33.648 ;
    LAYER M4 ;
    RECT 0 0 24.709 33.648 ;
  END
END fakeram_82x160_1r1w

END LIBRARY
